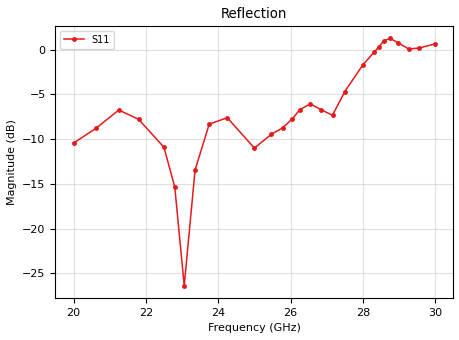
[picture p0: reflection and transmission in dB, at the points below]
! freq	mag(S11)	phase(S11)
!ADF5904 RF2
#  Hz  S  MA  R 50
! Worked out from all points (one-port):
!   1001 points, 20 GHz to 30 GHz, reference 50 ohm
!   lowest |S11| = -26.4 dB at 23.06 GHz (marker M1), VSWR 1.10, Z = 54.5 + j2.15 ohm
!   |S11| at or under -10 dB: start of sweep to 20.42 GHz; 22.37 GHz to 23.56 GHz (1.189 GHz wide, 5.18 % of centre); 24.69 GHz to 25.31 GHz (615.8 MHz wide, 2.46 % of centre)
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2e10  0.3004 61.7
2.063e10  0.3645 24.9
2.125e10  0.4599 35.7
2.18e10  0.408 64.1
2.25e10  0.2847 82.6
2.28e10  0.1701 86.4
2.306e10  0.04791 24.3
2.336e10  0.2122 -30.0
2.375e10  0.3833 -7.5
2.425e10  0.4166 27.3
2.5e10  0.2817 100.4
2.547e10  0.3368 142.5
2.578e10  0.3656 -171.2
2.605e10  0.4103 -115.7
2.625e10  0.4611 -79.6
2.655e10  0.4981 -39.8
2.685e10  0.4607 -7.3
2.716e10  0.4301 38.8
2.75e10  0.5837 90.9
2.799e10  0.8178 120.8
2.83e10  0.9647 142.0
2.845e10  1.04 160.0
2.857e10  1.116 179.3
2.875e10  1.157 -146.4
2.897e10  1.094 -103.6
2.927e10  1.008 -60.0
2.956e10  1.023 -36.2
3e10  1.078 -8.1
